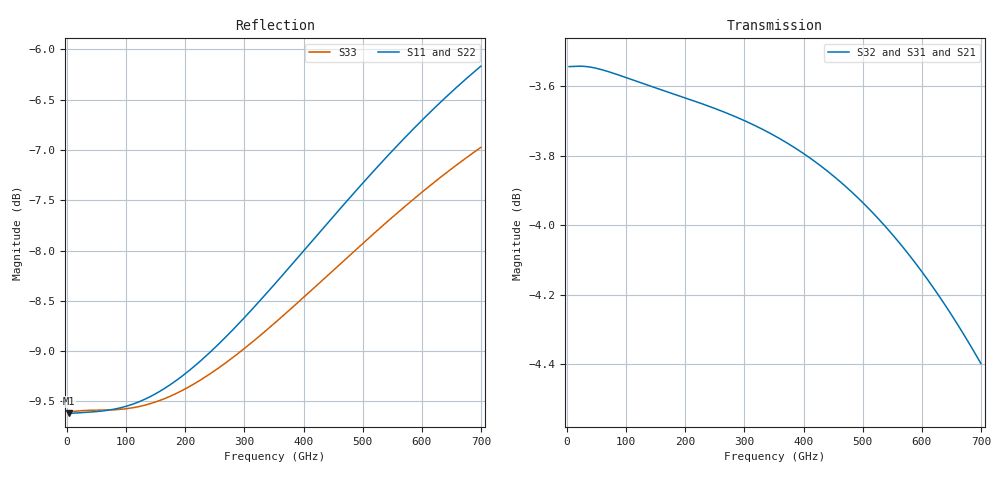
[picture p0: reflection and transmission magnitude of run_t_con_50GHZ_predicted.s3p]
#  Hz  S  RI  R  50
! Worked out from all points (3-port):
!   200 points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, 3.5 GHz to 700 GHz, reference 50 ohm
!   strongest paths, dB at 3.5 GHz, 178.5 GHz, 353.5 GHz, 528.5 GHz, 700 GHz:
!     S32: -3.5, -3.6, -3.7, -4.0, -4.4
!     S31: -3.5, -3.6, -3.7, -4.0, -4.4
!     S21: -3.6, -3.7, -3.9, -4.3, -4.8
!   lowest |S11| = -9.6 dB at 3.5 GHz (marker M1), VSWR 1.99, Z = 25.2 + j0.22 ohm
!   |S11| at or under -10 dB: nowhere
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3.5e9  -0.3304 0.0039  0.6644 -0.00335  0.665 -0.00268
       0.6644 -0.00335  -0.3304 0.0039  0.665 -0.00268
       0.665 -0.00268  0.665 -0.00268  -0.331 0.00323
3.85e10  -0.3281 0.043  0.6628 -0.0368  0.6643 -0.0301
         0.6628 -0.0368  -0.3281 0.043  0.6643 -0.0301
         0.6643 -0.0301  0.6643 -0.0301  -0.3296 0.0363
7.7e10  -0.3209 0.0847  0.658 -0.0728  0.6609 -0.0599
        0.658 -0.0729  -0.3209 0.0848  0.6609 -0.0599
        0.6609 -0.0599  0.6609 -0.0599  -0.3239 0.0717
1.715e11  -0.2904 0.1787  0.6366 -0.1564  0.6465 -0.1293
          0.6365 -0.1564  -0.2903 0.1789  0.6465 -0.1294
          0.6466 -0.1294  0.6466 -0.1294  -0.3006 0.1517
2.625e11  -0.247 0.2608  0.6051 -0.2312  0.6258 -0.1938
          0.6051 -0.2312  -0.2469 0.261  0.6257 -0.1939
          0.6259 -0.1939  0.6259 -0.194  -0.2681 0.2236
3.535e11  -0.1897 0.3336  0.5634 -0.2997  0.597 -0.256
          0.5633 -0.2996  -0.1895 0.3339  0.5969 -0.2561
          0.5971 -0.2563  0.597 -0.2564  -0.224 0.2906
4.445e11  -0.1196 0.3943  0.5121 -0.3602  0.5593 -0.3145
          0.5121 -0.3601  -0.1194 0.3945  0.5592 -0.3146
          0.5594 -0.3149  0.5593 -0.315  -0.1677 0.3497
5.32e11  -0.0424 0.4383  0.4552 -0.4092  0.5149 -0.3651
         0.4551 -0.4091  -0.0421 0.4386  0.5148 -0.3652
         0.5149 -0.3657  0.5149 -0.3658  -0.103 0.396
6.16e11  0.0376 0.4654  0.3951 -0.4464  0.4656 -0.4067
         0.395 -0.4463  0.038 0.4657  0.4655 -0.4067
         0.4655 -0.4074  0.4654 -0.4075  -0.0335 0.428
7e11  0.12 0.4768  0.3316 -0.4733  0.4113 -0.4399
      0.3316 -0.4732  0.1204 0.477  0.4111 -0.44
      0.411 -0.4408  0.4109 -0.4409  0.0402 0.4462
